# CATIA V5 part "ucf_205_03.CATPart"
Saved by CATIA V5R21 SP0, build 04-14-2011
Part number: ucf_205_03
Bounding box of the stored display mesh (mm): x -43.513 to -41.313, y -2.8 to -0.6, z -1.1 to 1.1
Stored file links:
  C:\TPO v2\SharedFS\Outgoing\ucf_205_03.CATPart

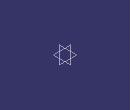
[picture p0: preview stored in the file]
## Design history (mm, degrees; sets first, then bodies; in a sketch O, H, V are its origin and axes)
AxisSystem1: origin (0, 0, 0), X (1, 0, 0), Y (0, 1, 0), Z (0, 0, 1)
Body1 "ucf_205_03" (main body)
  Solid1: solid without history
